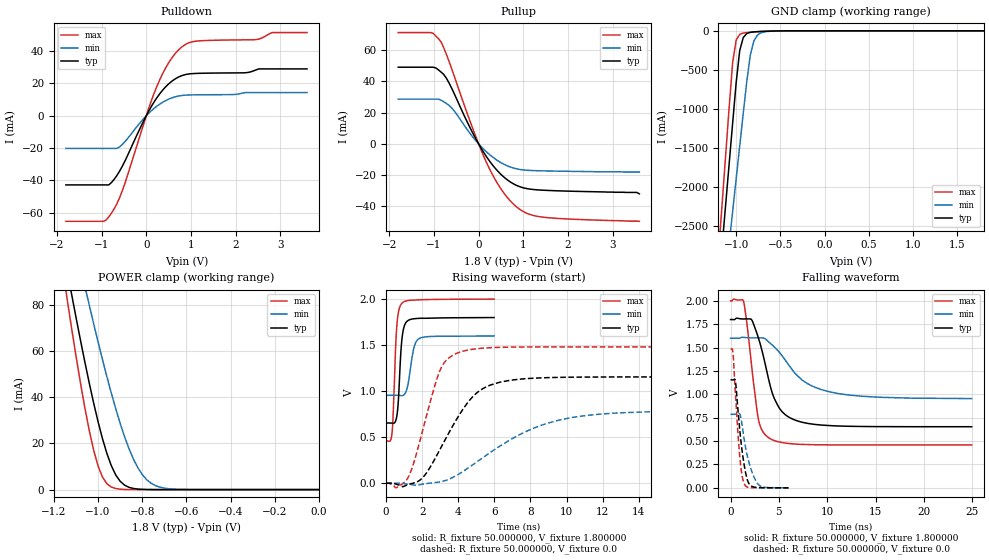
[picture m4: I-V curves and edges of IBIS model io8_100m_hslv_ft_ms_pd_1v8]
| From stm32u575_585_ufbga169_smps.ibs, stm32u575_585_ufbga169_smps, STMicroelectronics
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|   Model io8_100m_hslv_ft_ms_pd_1v8
[Model]  io8_100m_hslv_ft_ms_pd_1v8
Model_type I/O
Polarity   Non-Inverting
Enable   Active-Low
Vinl =   0.540000V
Vinh =   1.260000V
Vmeas =  0.900000V
Cref =   50.000000pF
Rref =   100.000000M
Vref =   0.0V
C_comp   3.235100pF   3.233200pF   3.282800pF
[Temperature Range]   25.000000   0.140000k   -40.000000
[Pullup Reference]   1.800000V   1.600000V   2.000000V
[Pulldown Reference]   0.0V   0.0V   0.0V
[POWER Clamp Reference]   1.800000V   1.600000V   2.000000V
[GND Clamp Reference]   0.0V   0.0V   0.0V
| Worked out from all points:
|   slope of the pulldown table from 0 to 0.27 V, typ, clamps not added: 21.7 ohm
|   slope of the pullup table from 0 to 0.27 V, typ, clamps not added: 22.6 ohm
|   GND clamp passes 1 mA (typ) near -0.51 V on its own axis
|   POWER clamp passes 1 mA (typ) near -0.86 V on its own axis
|   rising waveform, R_fixture 50.000000, V_fixture 1.800000: 20-80 % time 207ps typ, 320ps min, 193ps max; typ from 0.654 V to 1.8 V
|   rising waveform, R_fixture 50.000000, V_fixture 0.0: 20-80 % time 2.12ns typ, 4.11ns min, 1.26ns max; typ from 0 V to 1.15 V
|   falling waveform, R_fixture 50.000000, V_fixture 1.800000: 20-80 % time 1.9ns typ, 3.69ns min, 1.06ns max; typ from 1.8 V to 0.654 V
|   falling waveform, R_fixture 50.000000, V_fixture 0.0: 20-80 % time 740ps typ, 1.01ns min, 587ps max; typ from 1.15 V to 0 V
[Pulldown]
|Voltage   I(typ)   I(min)   I(max)
-1.8V     -42.74mA   -20.21mA   -65.25mA
-960mV    -42.74mA   -20.21mA   -65.25mA
-780mV    -41.3mA    -20.21mA   -60.25mA
-540mV    -31.39mA   -17.82mA   -46.65mA
0V        0A         -500fA     0A
240mV     11.28mA    6.002mA    18.38mA
480mV     19.17mA    10.02mA    31.83mA
780mV     24.67mA    12.5mA     42.21mA
1.14V     26.24mA    12.99mA    46.23mA
2.46V     28.42mA    14.39mA    47.14mA
2.82V     29mA       14.39mA    51.49mA
3.6V      29mA       14.39mA    51.49mA
[Pullup]
|Voltage   I(typ)   I(min)   I(max)
-1.8V     49.08mA    28.63mA    71.26mA
-1.08V    49.08mA    28.63mA    71.26mA
-840mV    45.95mA    27.95mA    65.26mA
-720mV    41.97mA    25.84mA    57.25mA
-600mV    35.46mA    22.93mA    47.86mA
-180mV    9.685mA    6.268mA    13.58mA
180mV     -8.368mA   -5.234mA   -12.14mA
540mV     -20.62mA   -12.68mA   -30.5mA
900mV     -27.22mA   -16.28mA   -41.49mA
1.14V     -28.94mA   -17mA      -45.14mA
1.5V      -29.77mA   -17.34mA   -47.14mA
3.6V      -32mA      -18mA      -49.6mA
[GND_clamp]
|Voltage   I(typ)   I(min)   I(max)
-1.8V     -9.707A    -9.942A    -9.774A
-1.2V     -3.309A    -4.006A    -2.865A
-1.16V    -2.777A    -3.584A    -2.239A
-1.12V    -2.246A    -3.162A    -1.614A
-1.04V    -1.186A    -2.319A    -408.7mA
-1V       -663.9mA   -1.898A    -117.8mA
-960mV    -254mA     -1.478A    -45.15mA
-920mV    -86.04mA   -1.06A     -28.6mA
-840mV    -19.13mA   -308.9mA   -18.75mA
-800mV    -13.4mA    -130.8mA   -15.33mA
-720mV    -7.959mA   -25.38mA   -9.395mA
1.8V      45.71uA    33.33uA    56.11uA
[POWER_clamp]
|Voltage   I(typ)   I(min)   I(max)
-1.8V     470.8mA    433.7mA    554.6mA
-1.14V    95.25mA    122.7mA    82.82mA
-1.12V    84.97mA    114mA      70.27mA
-1.06V    55.51mA    88.42mA    35.67mA
-1.04V    46.34mA    80.15mA    25.76mA
-1V       29.51mA    64.13mA    10.3mA
-940mV    10.39mA    41.86mA    1.109mA
-900mV    3.624mA    28.77mA    182.8uA
-840mV    490.7uA    13.24mA    11.35uA
-800mV    116.8uA    6.532mA    1.77uA
-740mV    13.2uA     1.723mA    109.2nA
0V        0A         18.72nA    0A
[Ramp]
| variable   typ   min   max
dV/dt_r  0.69258/2.11561n   0.47166/4.10833n   0.88824/1.25611n
dV/dt_f  0.68753/1.89816n   0.38638/3.68861n   0.92451/1.05360n
R_load = 50.000000
[Rising Waveform]
R_fixture= 50.000000
V_fixture= 1.800000
V_fixture_min= 1.600000
V_fixture_max= 2.000000
|time   V(typ)   V(min)   V(max)
0s        653.5mV    954.4mV    458.5mV
324.3ps   652.2mV    954.5mV    542.6mV
384.4ps   650.4mV    954.6mV    733.3mV
588.6ps   725.8mV    954.7mV    1.702V
684.7ps   923.2mV    954.3mV    1.862V
852.9ps   1.521V     950.9mV    1.949V
1.105ns   1.747V     997.4mV    1.979V
1.55ns    1.786V     1.479V     1.988V
1.838ns   1.791V     1.572V     1.992V
5.982ns   1.799V     1.599V     1.999V
[Rising Waveform]
R_fixture= 50.000000
V_fixture= 0.0
V_fixture_min= 0.0
V_fixture_max= 0.0
|time   V(typ)   V(min)   V(max)
0s        -90.96uV   -18.92uV   -77.39uV
550.6ps   -10.41mV   -58.52uV   -50.74mV
1.201ns   -16.55mV   -11.09mV   57.53mV
2.052ns   65.95mV    -8.993mV   595.3mV
2.953ns   355.7mV    13.27mV    1.211V
4.154ns   772.8mV    114.4mV    1.428V
5.055ns   985.9mV    235.1mV    1.461V
6.106ns   1.086V     378.1mV    1.475V
10.56ns   1.152V     721.4mV    1.48V
24.92ns   1.155V     786.3mV    1.48V
[Falling Waveform]
R_fixture= 50.000000
V_fixture= 1.800000
V_fixture_min= 1.600000
V_fixture_max= 2.000000
|time   V(typ)   V(min)   V(max)
0s        1.799V     1.599V     1.999V
1.351ns   1.806V     1.609V     1.992V
2.152ns   1.801V     1.603V     1.329V
2.853ns   1.611V     1.604V     748.6mV
4.054ns   1.11V      1.55V      528.2mV
4.805ns   896.7mV    1.477V     496.3mV
5.656ns   782.5mV    1.366V     478.6mV
7.357ns   702.4mV    1.156V     464.7mV
9.409ns   671.2mV    1.05V      460mV
24.92ns   653.5mV    954.4mV    458.5mV
[Falling Waveform]
R_fixture= 50.000000
V_fixture= 0.0
V_fixture_min= 0.0
V_fixture_max= 0.0
|time   V(typ)   V(min)   V(max)
0s        1.155V     786.3mV    1.48V
240.2ps   1.154V     786.3mV    1.452V
492.5ps   1.144V     786.5mV    1.018V
768.8ps   829.6mV    789.4mV    575.7mV
973ps     599.1mV    787mV      313.4mV
1.189ns   399.9mV    673.5mV    131.5mV
1.393ns   254.7mV    528.7mV    50.36mV
1.886ns   48.23mV    276.8mV    4.615mV
2.823ns   3.338mV    42.85mV    1.237mV
5.982ns   -90.96uV   -18.92uV   -77.39uV
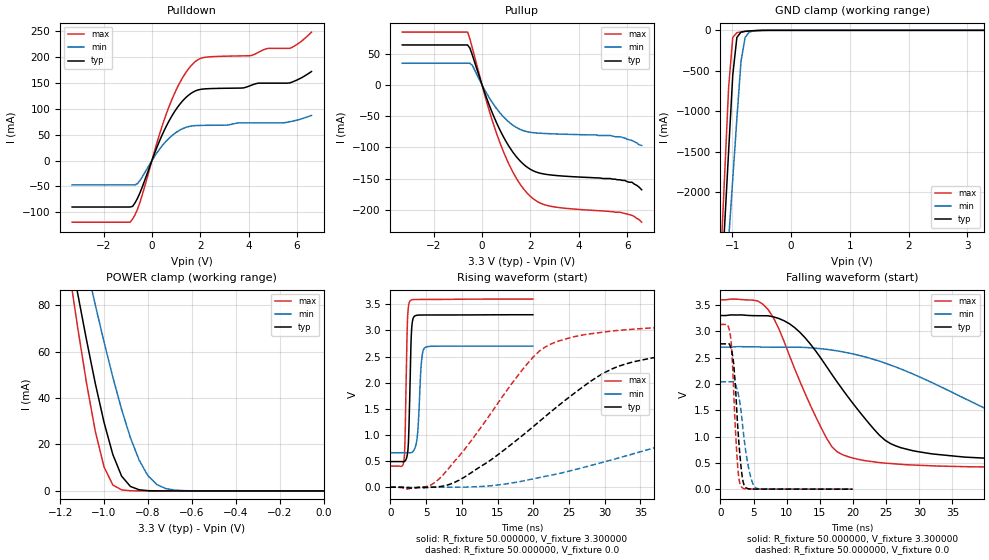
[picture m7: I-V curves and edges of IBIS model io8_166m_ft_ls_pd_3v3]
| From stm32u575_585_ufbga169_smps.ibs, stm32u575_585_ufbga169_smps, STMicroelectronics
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|   Model io8_166m_ft_ls_pd_3v3
[Model]  io8_166m_ft_ls_pd_3v3
Model_type I/O
Polarity   Non-Inverting
Enable   Active-Low
Vinl =   0.990000V
Vinh =   2.310000V
Vmeas =  1.650000V
Cref =   50.000000pF
Rref =   100.000000M
Vref =   0.0V
C_comp   3.517100pF   3.489300pF   3.557700pF
[Temperature Range]   25.000000   0.140000k   -40.000000
[Pullup Reference]   3.300000V   2.700000V   3.600000V
[Pulldown Reference]   0.0V   0.0V   0.0V
[POWER Clamp Reference]   3.300000V   2.700000V   3.600000V
[GND Clamp Reference]   0.0V   0.0V   0.0V
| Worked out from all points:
|   slope of the pulldown table from 0 to 0.495 V, typ, clamps not added: 8.73 ohm
|   slope of the pullup table from 0 to 0.495 V, typ, clamps not added: 9.64 ohm
|   GND clamp passes 1 mA (typ) near -0.50 V on its own axis
|   POWER clamp passes 1 mA (typ) near -0.85 V on its own axis
|   rising waveform, R_fixture 50.000000, V_fixture 3.300000: 20-80 % time 307ps typ, 454ps min, 272ps max; typ from 0.49 V to 3.3 V
|   rising waveform, R_fixture 50.000000, V_fixture 0.0: 20-80 % time 15.9ns typ, 34.2ns min, 10.3ns max; typ from 0 V to 2.76 V
|   falling waveform, R_fixture 50.000000, V_fixture 3.300000: 20-80 % time 10.1ns typ, 22.3ns min, 6.6ns max; typ from 3.3 V to 0.49 V
|   falling waveform, R_fixture 50.000000, V_fixture 0.0: 20-80 % time 897ps typ, 1.3ns min, 735ps max; typ from 2.76 V to 0 V
[Pulldown]
|Voltage   I(typ)   I(min)   I(max)
-3.3V     -89.72mA   -47.06mA   -119mA
-900mV    -89.72mA   -47.06mA   -119mA
-500mV    -62.92mA   -38.71mA   -81.44mA
300mV     36.2mA     21.01mA    48.7mA
800mV     84.07mA    46.96mA    114.9mA
1.3V      116.7mA    62.09mA    162.4mA
1.8V      134.4mA    67.39mA    191.2mA
2.3V      138.6mA    67.98mA    199.8mA
4.1V      145.1mA    72.78mA    202.7mA
4.8V      149.4mA    72.78mA    216.5mA
5.7V      149.8mA    74.8mA     216.5mA
6.6V      171.9mA    87.1mA     247.9mA
[Pullup]
|Voltage   I(typ)   I(min)   I(max)
-3.3V     64.11mA    34.77mA    84.74mA
-600mV    64.11mA    34.77mA    84.74mA
-400mV    47.78mA    31.25mA    59.06mA
300mV     -32.62mA   -20.62mA   -41.63mA
800mV     -76.87mA   -47.45mA   -98.74mA
1.4V      -114.1mA   -67.68mA   -148.3mA
1.7V      -126.6mA   -73.14mA   -165.7mA
2.1V      -137.3mA   -76.42mA   -182mA
3V        -144.9mA   -78.48mA   -195.5mA
5.9V      -153mA     -85mA      -206mA
6.2V      -156mA     -89mA      -209mA
6.6V      -168mA     -97mA      -220mA
[GND_clamp]
|Voltage   I(typ)   I(min)   I(max)
-3.3V     -9.098A    -9.372A    -9.671A
-1.2V     -3.386A    -4.091A    -2.933A
-1.13V    -2.437A    -3.34A     -1.815A
-1.06V    -1.49A     -2.588A    -705.6mA
-990mV    -555.7mA   -1.839A    -89.05mA
-920mV    -88.14mA   -1.093A    -28.79mA
-850mV    -22.37mA   -387.4mA   -19.86mA
-780mV    -12.13mA   -88.01mA   -13.89mA
-710mV    -7.72mA    -22.53mA   -8.86mA
-640mV    -4.556mA   -7.872mA   -4.884mA
-360mV    -39.7uA    -179.9uA   -19.45uA
3.28V     83.52uA    56.87uA    102.4uA
[POWER_clamp]
|Voltage   I(typ)   I(min)   I(max)
-3.28V    1.355A     1.167A     1.664A
-1.16V    105.7mA    131.6mA    95.69mA
-1.12V    84.97mA    114mA      70.27mA
-1.08V    65.05mA    96.83mA    46.54mA
-1.04V    46.34mA    80.15mA    25.76mA
-1V       29.51mA    64.13mA    10.3mA
-960mV    15.69mA    48.99mA    2.571mA
-920mV    6.373mA    35.1mA     455.6uA
-840mV    490.7uA    13.24mA    11.36uA
-760mV    27.33uA    2.767mA    278.2nA
-640mV    347.6nA    134.1uA    16.76nA
0V        0A         19.95nA    0A
[Ramp]
| variable   typ   min   max
dV/dt_r  1.65672/15.83283n   1.22418/34.20511n   1.87818/10.27070n
dV/dt_f  1.68577/10.07893n   1.22392/22.27950n   1.91752/6.57604n
R_load = 50.000000
[Rising Waveform]
R_fixture= 50.000000
V_fixture= 3.300000
V_fixture_min= 2.700000
V_fixture_max= 3.600000
|time   V(typ)   V(min)   V(max)
0s        489.8mV    659.5mV    403.4mV
1.922ns   489.5mV    659.5mV    523.7mV
2.042ns   498.3mV    659.5mV    806.3mV
2.402ns   639.8mV    659.3mV    3.175V
2.763ns   1.96V      658.3mV    3.562V
3.123ns   3.191V     676.2mV    3.588V
3.764ns   3.29V      946.9mV    3.591V
4.364ns   3.294V     2.402V     3.592V
4.845ns   3.294V     2.67V      3.592V
19.94ns   3.299V     2.699V     3.599V
[Rising Waveform]
R_fixture= 50.000000
V_fixture= 0.0
V_fixture_min= 0.0
V_fixture_max= 0.0
|time   V(typ)   V(min)   V(max)
0s        15.39nV    112.3nV    48.72nV
6.406ns   3.48mV     -601.2uV   105.4mV
13.61ns   478mV      20.14mV    1.322V
18.42ns   981.5mV    115.1mV    2.236V
21.62ns   1.346V     206.1mV    2.678V
29.63ns   2.168V     472.6mV    2.964V
36.84ns   2.477V     750.2mV    3.049V
63.26ns   2.712V     1.657V     3.121V
95.3ns    2.754V     1.937V     3.129V
398.8ns   2.761V     2.04V      3.13V
[Falling Waveform]
R_fixture= 50.000000
V_fixture= 3.300000
V_fixture_min= 2.700000
V_fixture_max= 3.600000
|time   V(typ)   V(min)   V(max)
0s        3.299V     2.699V     3.599V
5.606ns   3.296V     2.704V     3.578V
7.207ns   3.295V     2.698V     3.412V
12.01ns   2.978V     2.696V     2.042V
17.62ns   2.035V     2.628V     709.6mV
24.02ns   1.02V      2.43V      504.3mV
28.03ns   761.9mV    2.242V     464.7mV
49.65ns   540.7mV    1.059V     410.4mV
81.68ns   498.4mV    756.2mV    404.1mV
398.8ns   489.8mV    659.5mV    403.4mV
[Falling Waveform]
R_fixture= 50.000000
V_fixture= 0.0
V_fixture_min= 0.0
V_fixture_max= 0.0
|time   V(typ)   V(min)   V(max)
0s        2.761V     2.04V      3.13V
1.001ns   2.761V     2.04V      3.133V
1.522ns   2.707V     2.04V      2.907V
2.002ns   2.376V     2.044V     1.864V
2.563ns   1.293V     1.882V     509.3mV
2.843ns   794.5mV    1.715V     165.3mV
3.203ns   321.5mV    1.38V      37.65mV
4.244ns   7.792mV    410.8mV    2.284mV
5.325ns   1.171mV    26.6mV     1.552mV
19.94ns   15.39nV    112.3nV    48.72nV
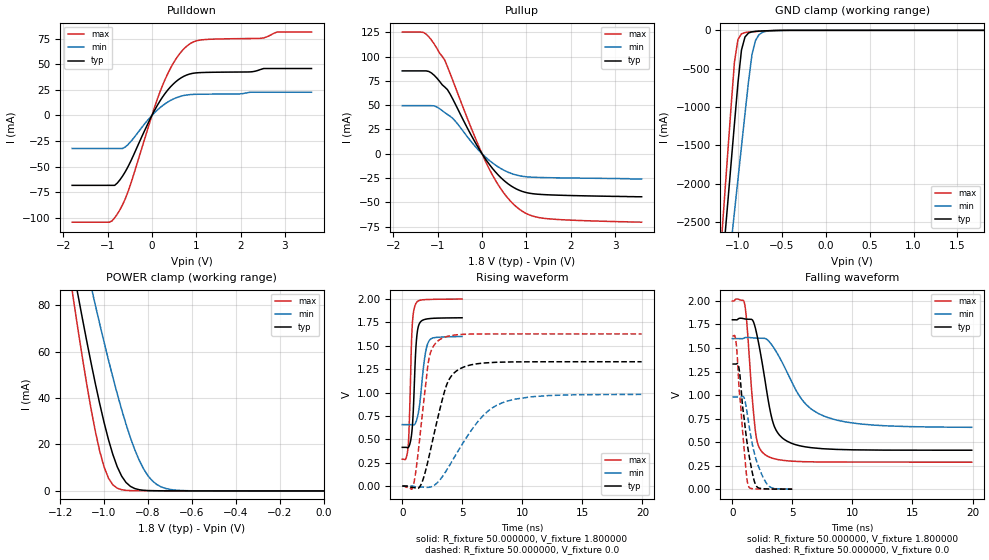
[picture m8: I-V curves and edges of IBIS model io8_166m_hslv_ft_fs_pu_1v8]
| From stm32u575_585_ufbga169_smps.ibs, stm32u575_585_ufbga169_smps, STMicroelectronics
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|   Model io8_166m_hslv_ft_fs_pu_1v8
[Model]  io8_166m_hslv_ft_fs_pu_1v8
Model_type I/O
Polarity   Non-Inverting
Enable   Active-Low
Vinl =   0.540000V
Vinh =   1.260000V
Vmeas =  0.900000V
Cref =   50.000000pF
Rref =   100.000000M
Vref =   0.0V
C_comp   3.358400pF   3.352800pF   3.400400pF
[Temperature Range]   25.000000   0.140000k   -40.000000
[Pullup Reference]   1.800000V   1.600000V   2.000000V
[Pulldown Reference]   0.0V   0.0V   0.0V
[POWER Clamp Reference]   1.800000V   1.600000V   2.000000V
[GND Clamp Reference]   0.0V   0.0V   0.0V
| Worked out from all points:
|   slope of the pulldown table from 0 to 0.27 V, typ, clamps not added: 13.6 ohm
|   slope of the pullup table from 0 to 0.27 V, typ, clamps not added: 15.9 ohm
|   GND clamp passes 1 mA (typ) near -0.51 V on its own axis
|   POWER clamp passes 1 mA (typ) near -0.86 V on its own axis
|   rising waveform, R_fixture 50.000000, V_fixture 1.800000: 20-80 % time 290ps typ, 497ps min, 236ps max; typ from 0.414 V to 1.8 V
|   rising waveform, R_fixture 50.000000, V_fixture 0.0: 20-80 % time 1.51ns typ, 3.17ns min, 854ps max; typ from 0 V to 1.33 V
|   falling waveform, R_fixture 50.000000, V_fixture 1.800000: 20-80 % time 1.2ns typ, 2.76ns min, 637ps max; typ from 1.8 V to 0.414 V
|   falling waveform, R_fixture 50.000000, V_fixture 0.0: 20-80 % time 791ps typ, 1.05ns min, 592ps max; typ from 1.33 V to 0 V
[Pulldown]
|Voltage   I(typ)   I(min)   I(max)
-1.8V     -68.38mA   -32.32mA   -104.4mA
-960mV    -68.38mA   -32.32mA   -104.4mA
-780mV    -66.08mA   -32.32mA   -96.43mA
-540mV    -50.22mA   -28.51mA   -74.66mA
0V        0A         0A         0A
240mV     18.04mA    9.6mA      29.42mA
480mV     30.68mA    16.02mA    50.95mA
780mV     39.48mA    19.99mA    67.56mA
1.14V     41.99mA    20.78mA    74.01mA
2.46V     45.1mA     22.69mA    75.45mA
2.82V     45.89mA    22.69mA    81.54mA
3.6V      45.89mA    22.69mA    81.54mA
[Pullup]
|Voltage   I(typ)   I(min)   I(max)
-1.8V     85.36mA    49.56mA    125.3mA
-1.32V    85.36mA    49.56mA    124.9mA
-1.08V    80.85mA    49.29mA    113.1mA
-840mV    68.7mA     42.35mA    96.38mA
-660mV    56.31mA    36.42mA    75.5mA
-180mV    13.77mA    8.913mA    19.32mA
180mV     -11.9mA    -7.442mA   -17.26mA
480mV     -26.98mA   -16.65mA   -39.76mA
840mV     -37.65mA   -22.63mA   -57.07mA
1.08V     -40.74mA   -24.01mA   -63.22mA
1.44V     -42.19mA   -24.58mA   -66.73mA
3.6V      -44.3mA    -26mA      -70.5mA
[GND_clamp]
|Voltage   I(typ)   I(min)   I(max)
-1.8V     -9.908A    -9.683A    -9.994A
-1.2V     -3.383A    -4.084A    -2.934A
-1.16V    -2.841A    -3.655A    -2.294A
-1.12V    -2.299A    -3.226A    -1.656A
-1.04V    -1.218A    -2.369A    -414.2mA
-1V       -684.7mA   -1.941A    -119.2mA
-960mV    -257.2mA   -1.514A    -45.66mA
-920mV    -87.03mA   -1.089A    -28.93mA
-840mV    -19.35mA   -312.8mA   -18.97mA
-800mV    -13.55mA   -132.4mA   -15.49mA
-720mV    -8.042mA   -25.67mA   -9.491mA
1.8V      0A         13.64nA    0A
[POWER_clamp]
|Voltage   I(typ)   I(min)   I(max)
-1.8V     470.9mA    433.7mA    554.6mA
-1.14V    95.28mA    122.7mA    82.88mA
-1.12V    85mA       114mA      70.34mA
-1.06V    55.55mA    88.43mA    35.73mA
-1.04V    46.38mA    80.17mA    25.83mA
-1V       29.54mA    64.14mA    10.37mA
-940mV    10.43mA    41.88mA    1.177mA
-900mV    3.66mA     28.79mA    250.5uA
-840mV    527.2uA    13.26mA    96.07uA
-800mV    154.2uA    6.55mA     88.1uA
-740mV    59.7uA     1.741mA    70.27uA
0V        0A         18.18nA    0A
[Ramp]
| variable   typ   min   max
dV/dt_r  0.79757/1.50753n   0.58780/3.16215n   0.97651/0.85245n
dV/dt_f  0.83132/1.19679n   0.56443/2.75362n   1.02743/0.63550n
R_load = 50.000000
[Rising Waveform]
R_fixture= 50.000000
V_fixture= 1.800000
V_fixture_min= 1.600000
V_fixture_max= 2.000000
|time   V(typ)   V(min)   V(max)
0s        414.4mV    657.5mV    287.7mV
500.5ps   413.3mV    657.7mV    438.2mV
590.6ps   433.7mV    657.7mV    696mV
810.8ps   592.5mV    656.4mV    1.663V
1.071ns   1.308V     666.2mV    1.934V
1.191ns   1.574V     702.8mV    1.964V
1.371ns   1.72V      805.8mV    1.983V
1.862ns   1.782V     1.367V     1.994V
2.192ns   1.79V      1.544V     1.996V
4.985ns   1.8V       1.6V       2V
[Rising Waveform]
R_fixture= 50.000000
V_fixture= 0.0
V_fixture_min= 0.0
V_fixture_max= 0.0
|time   V(typ)   V(min)   V(max)
0s        398.4uV    503.2uV    379.2uV
920.9ps   -14.26mV   -1.108mV   5.419mV
1.562ns   15.92mV    -10.29mV   636.8mV
2.202ns   301.5mV    -12.82mV   1.346V
3.123ns   816.4mV    64.35mV    1.567V
3.764ns   1.103V     184.7mV    1.602V
4.484ns   1.228V     340mV      1.617V
6.607ns   1.314V     735.9mV    1.627V
8.328ns   1.326V     890.7mV    1.628V
19.94ns   1.33V      980.7mV    1.628V
[Falling Waveform]
R_fixture= 50.000000
V_fixture= 1.800000
V_fixture_min= 1.600000
V_fixture_max= 2.000000
|time   V(typ)   V(min)   V(max)
0s        1.8V       1.6V       2V
1.001ns   1.81V      1.608V     1.98V
1.201ns   1.807V     1.613V     1.77V
1.962ns   1.687V     1.605V     576.1mV
2.763ns   1.12V      1.6V       363.3mV
3.323ns   735.4mV    1.525V     329.8mV
3.924ns   574.4mV    1.401V     312.2mV
5.846ns   455.3mV    943.9mV    292.7mV
7.808ns   428.1mV    767.4mV    288.9mV
19.94ns   414.4mV    657.5mV    287.7mV
[Falling Waveform]
R_fixture= 50.000000
V_fixture= 0.0
V_fixture_min= 0.0
V_fixture_max= 0.0
|time   V(typ)   V(min)   V(max)
0s        1.33V      980.7mV    1.628V
300.3ps   1.33V      980.8mV    1.566V
400.4ps   1.335V     980.8mV    1.428V
530.5ps   1.3V       980.8mV    1.129V
981ps     750.8mV    970.5mV    423.2mV
1.191ns   525.5mV    840.2mV    133.6mV
1.341ns   397mV      715.9mV    33mV
1.952ns   43.7mV     326.2mV    3.268mV
2.773ns   3.59mV     75.49mV    1.456mV
4.985ns   398.4uV    503.2uV    379.2uV
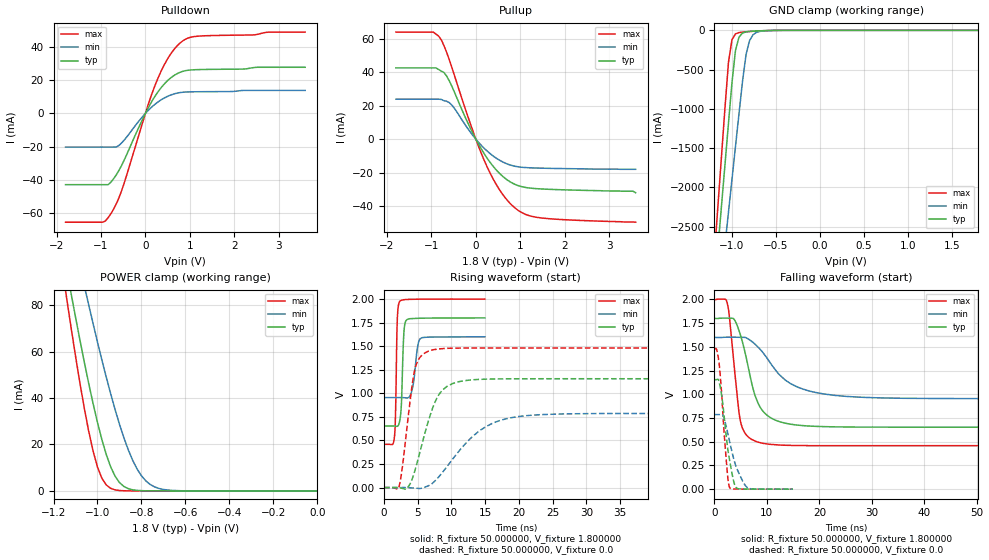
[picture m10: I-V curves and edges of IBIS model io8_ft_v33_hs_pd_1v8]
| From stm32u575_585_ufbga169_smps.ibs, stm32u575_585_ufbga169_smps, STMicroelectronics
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|   Model io8_ft_v33_hs_pd_1v8
[Model]  io8_ft_v33_hs_pd_1v8
Model_type I/O
Polarity   Non-Inverting
Enable   Active-Low
Vinl =   0.540000V
Vinh =   1.260000V
Vmeas =  0.900000V
Cref =   50.000000pF
Rref =   100.000000M
Vref =   0.0V
C_comp   3.087500pF   3.086600pF   3.135700pF
[Temperature Range]   25.000000   0.140000k   -40.000000
[Pullup Reference]   1.800000V   1.600000V   2.000000V
[Pulldown Reference]   0.0V   0.0V   0.0V
[POWER Clamp Reference]   1.800000V   1.600000V   2.000000V
[GND Clamp Reference]   0.0V   0.0V   0.0V
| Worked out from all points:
|   slope of the pulldown table from 0 to 0.27 V, typ, clamps not added: 21.7 ohm
|   slope of the pullup table from 0 to 0.27 V, typ, clamps not added: 22.6 ohm
|   GND clamp passes 1 mA (typ) near -0.51 V on its own axis
|   POWER clamp passes 1 mA (typ) near -0.86 V on its own axis
|   rising waveform, R_fixture 50.000000, V_fixture 1.800000: 20-80 % time 317ps typ, 630ps min, 229ps max; typ from 0.654 V to 1.8 V
|   rising waveform, R_fixture 50.000000, V_fixture 0.0: 20-80 % time 2.89ns typ, 6.11ns min, 1.52ns max; typ from 0 V to 1.15 V
|   falling waveform, R_fixture 50.000000, V_fixture 1.800000: 20-80 % time 3.27ns typ, 6.78ns min, 1.71ns max; typ from 1.8 V to 0.654 V
|   falling waveform, R_fixture 50.000000, V_fixture 0.0: 20-80 % time 1.6ns typ, 2.38ns min, 1.14ns max; typ from 1.15 V to 0 V
[Pulldown]
|Voltage   I(typ)   I(min)   I(max)
-1.8V     -42.74mA   -20.21mA   -65.25mA
-960mV    -42.74mA   -20.21mA   -65.25mA
-780mV    -41.3mA    -20.21mA   -60.25mA
-660mV    -37mA      -20.2mA    -54.5mA
-540mV    -31.39mA   -17.82mA   -46.65mA
0V        0A         0A         0A
240mV     11.28mA    6.002mA    18.38mA
480mV     19.17mA    10.02mA    31.83mA
780mV     24.67mA    12.5mA     42.21mA
960mV     25.9mA     12.9mA     45.21mA
1.14V     26.24mA    12.99mA    46.23mA
3.6V      27.69mA    13.82mA    48.79mA
[Pullup]
|Voltage   I(typ)   I(min)   I(max)
-1.8V     42.59mA    23.91mA    63.97mA
-960mV    42.59mA    23.91mA    63.97mA
-780mV    40.7mA     23.74mA    59.39mA
-660mV    37.78mA    22.66mA    52mA
-540mV    31.58mA    20.34mA    42.81mA
-120mV    6.338mA    4.065mA    8.965mA
180mV     -8.368mA   -5.234mA   -12.14mA
540mV     -20.62mA   -12.68mA   -30.5mA
900mV     -27.22mA   -16.28mA   -41.49mA
1.14V     -28.94mA   -17mA      -45.14mA
1.5V      -29.77mA   -17.34mA   -47.14mA
3.6V      -32mA      -18mA      -49.6mA
[GND_clamp]
|Voltage   I(typ)   I(min)   I(max)
-1.8V     -9.707A    -9.942A    -9.774A
-1.2V     -3.309A    -4.006A    -2.865A
-1.16V    -2.777A    -3.584A    -2.239A
-1.12V    -2.246A    -3.162A    -1.614A
-1.04V    -1.186A    -2.319A    -408.7mA
-1V       -663.9mA   -1.898A    -117.8mA
-960mV    -254mA     -1.478A    -45.15mA
-920mV    -86.04mA   -1.06A     -28.6mA
-840mV    -19.13mA   -308.9mA   -18.75mA
-800mV    -13.4mA    -130.8mA   -15.33mA
-720mV    -7.959mA   -25.38mA   -9.395mA
1.8V      45.71uA    33.33uA    56.11uA
[POWER_clamp]
|Voltage   I(typ)   I(min)   I(max)
-1.8V     470.8mA    433.7mA    554.6mA
-1.14V    95.25mA    122.7mA    82.82mA
-1.12V    84.97mA    114mA      70.27mA
-1.06V    55.51mA    88.42mA    35.67mA
-1.04V    46.34mA    80.15mA    25.76mA
-1V       29.51mA    64.13mA    10.3mA
-940mV    10.39mA    41.86mA    1.109mA
-900mV    3.624mA    28.77mA    182.8uA
-840mV    490.7uA    13.24mA    11.35uA
-800mV    116.8uA    6.532mA    1.77uA
-740mV    13.2uA     1.723mA    109.3nA
0V        0A         18.72nA    0A
[Ramp]
| variable   typ   min   max
dV/dt_r  0.69258/2.88459n   0.47170/6.10262n   0.88830/1.51750n
dV/dt_f  0.68753/3.27006n   0.38693/6.77240n   0.92451/1.71172n
R_load = 50.000000
[Rising Waveform]
R_fixture= 50.000000
V_fixture= 1.800000
V_fixture_min= 1.600000
V_fixture_max= 2.000000
|time   V(typ)   V(min)   V(max)
0s        653.5mV    954.4mV    458.5mV
1.562ns   653mV      954.4mV    540.9mV
1.712ns   651.7mV    954.5mV    778.9mV
1.982ns   650.3mV    954.5mV    1.791V
2.342ns   710mV      954.4mV    1.975V
2.583ns   884.8mV    954.2mV    1.987V
2.943ns   1.63V      953.3mV    1.992V
3.333ns   1.776V     950.4mV    1.995V
5.345ns   1.796V     1.576V     1.998V
14.95ns   1.799V     1.599V     1.999V
[Rising Waveform]
R_fixture= 50.000000
V_fixture= 0.0
V_fixture_min= 0.0
V_fixture_max= 0.0
|time   V(typ)   V(min)   V(max)
0s        4.575uV    -1.131uV   13.19uV
2.242ns   -3.065mV   5.74uV     10.23mV
3.524ns   3.056mV    -685.9uV   709.3mV
4.645ns   194.7mV    -6.053mV   1.274V
7.207ns   841.6mV    46.63mV    1.46V
8.328ns   1.004V     130.5mV    1.472V
10.25ns   1.105V     308.4mV    1.478V
14.41ns   1.148V     614.3mV    1.48V
19.86ns   1.154V     752.2mV    1.48V
79.76ns   1.154V     786.2mV    1.48V
[Falling Waveform]
R_fixture= 50.000000
V_fixture= 1.800000
V_fixture_min= 1.600000
V_fixture_max= 2.000000
|time   V(typ)   V(min)   V(max)
0s        1.799V     1.599V     1.999V
2.402ns   1.803V     1.602V     1.969V
2.883ns   1.802V     1.602V     1.804V
3.684ns   1.795V     1.602V     1.347V
4.965ns   1.625V     1.601V     714.9mV
6.086ns   1.379V     1.595V     571.2mV
8.168ns   926.4mV    1.505V     497.9mV
13.61ns   694.2mV    1.145V     462.8mV
20.66ns   659.7mV    1.005V     458.8mV
79.76ns   653.5mV    954.4mV    458.5mV
[Falling Waveform]
R_fixture= 50.000000
V_fixture= 0.0
V_fixture_min= 0.0
V_fixture_max= 0.0
|time   V(typ)   V(min)   V(max)
0s        1.154V     786.2mV    1.48V
420.4ps   1.154V     786.2mV    1.471V
930.9ps   1.123V     786mV      1.307V
1.622ns   887.7mV    779.1mV    785.5mV
2.372ns   500mV      632mV      230.8mV
2.673ns   376.1mV    557.7mV    68.41mV
2.943ns   290.1mV    490.2mV    12.75mV
4.024ns   25.08mV    255mV      1.526mV
6.276ns   1.141mV    16.69mV    507.6uV
14.95ns   4.575uV    -1.131uV   13.19uV
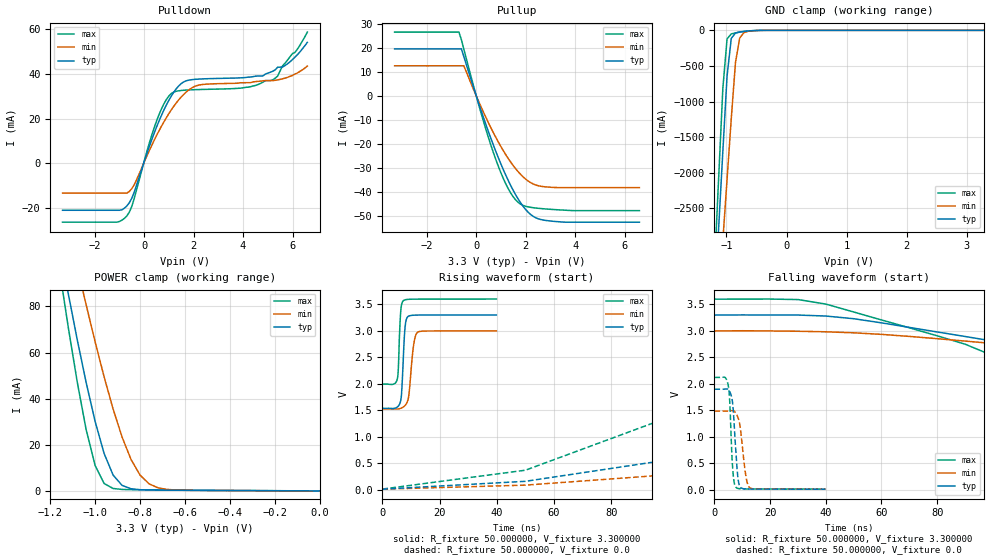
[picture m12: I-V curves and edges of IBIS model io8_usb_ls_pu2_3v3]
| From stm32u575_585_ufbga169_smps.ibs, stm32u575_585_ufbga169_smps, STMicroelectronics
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|   Model io8_usb_ls_pu2_3v3
[Model]  io8_usb_ls_pu2_3v3
Model_type I/O
Polarity   Non-Inverting
Enable   Active-Low
Vinl =   0.990000V
Vinh =   2.310000V
Vmeas =  1.650000V
Cref =   50.000000pF
Rref =   100.000000M
Vref =   0.0V
C_comp   7.156600pF   7.055100pF   7.302500pF
[Temperature Range]   25.000000   0.140000k   -40.000000
[Pullup Reference]   3.300000V   3.000000V   3.600000V
[Pulldown Reference]   0.0V   0.0V   0.0V
[POWER Clamp Reference]   3.300000V   3.000000V   3.600000V
[GND Clamp Reference]   0.0V   0.0V   0.0V
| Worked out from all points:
|   slope of the pulldown table from 0 to 0.495 V, typ, clamps not added: 32.2 ohm
|   slope of the pullup table from 0 to 0.495 V, typ, clamps not added: 33.1 ohm
|   GND clamp passes 1 mA (typ) near -0.45 V on its own axis
|   POWER clamp passes 1 mA (typ) near -0.84 V on its own axis
|   rising waveform, R_fixture 50.000000, V_fixture 3.300000: 20-80 % time 960ps typ, 1.52ns min, 701ps max; typ from 1.54 V to 3.3 V
|   rising waveform, R_fixture 50.000000, V_fixture 0.0: 20-80 % time 90.2ns typ, 130ns min, 66.7ns max; typ from 0.016 V to 1.9 V
|   falling waveform, R_fixture 50.000000, V_fixture 3.300000: 20-80 % time 79.3ns typ, 126ns min, 50.7ns max; typ from 3.3 V to 1.54 V
|   falling waveform, R_fixture 50.000000, V_fixture 0.0: 20-80 % time 1.41ns typ, 1.93ns min, 1.05ns max; typ from 1.9 V to 0.016 V
[Pulldown]
|Voltage   I(typ)   I(min)   I(max)
-3.3V     -21.06mA   -13.39mA   -26.4mA
-1.1V     -21.06mA   -13.39mA   -26.4mA
-700mV    -19.13mA   -13.39mA   -23.61mA
-400mV    -12.95mA   -9.641mA   -15.76mA
200mV     7.166mA    5.401mA    8.653mA
700mV     21.41mA    16.54mA    24.29mA
1.1V      30.09mA    23.9mA     31.2mA
1.5V      35.65mA    29.65mA    32.56mA
2.3V      37.71mA    35.15mA    33.01mA
5.2V      41.15mA    36.98mA    37.32mA
5.9V      45.4mA     38.89mA    47.66mA
6.6V      54.1mA     43.5mA     58.7mA
[Pullup]
|Voltage   I(typ)   I(min)   I(max)
-3.3V     19.5mA     12.47mA    26.48mA
-700mV    19.5mA     12.47mA    26.48mA
-600mV    19.5mA     12.47mA    23.34mA
-500mV    16.3mA     12.47mA    19.38mA
200mV     -6.226mA   -4.703mA   -7.327mA
700mV     -20.66mA   -15.47mA   -23.79mA
1.2V      -33.12mA   -24.56mA   -36.72mA
1.5V      -39.4mA    -29.07mA   -42.08mA
1.7V      -42.99mA   -31.61mA   -44.36mA
2.2V      -49.35mA   -36.11mA   -46.39mA
2.7V      -51.65mA   -37.76mA   -46.97mA
6.6V      -52.57mA   -38.16mA   -47.77mA
[GND_clamp]
|Voltage   I(typ)   I(min)   I(max)
-3.3V     -9.287A    -9.833A    -9.745A
-1.2V     -3.857A    -4.664A    -3.345A
-1.13V    -2.774A    -3.805A    -2.072A
-1.06V    -1.695A    -2.947A    -813.1mA
-990mV    -641.8mA   -2.091A    -120.9mA
-920mV    -113.3mA   -1.238A    -49.89mA
-850mV    -36.8mA    -452mA     -36.31mA
-780mV    -22.65mA   -108.9mA   -26.22mA
-710mV    -15.23mA   -32.27mA   -17.43mA
-570mV    -5.119mA   -7.032mA   -4.907mA
-360mV    -90.45uA   -461.6uA   -25.95uA
3.28V     0A         40.32nA    -16.18nA
[POWER_clamp]
|Voltage   I(typ)   I(min)   I(max)
-3.28V    1.356A     1.167A     1.665A
-1.16V    106.4mA    132.1mA    96.52mA
-1.12V    85.6mA     114.5mA    71.06mA
-1.08V    65.66mA    97.31mA    47.29mA
-1.04V    46.92mA    80.61mA    26.47mA
-1V       30.05mA    64.57mA    10.98mA
-960mV    16.21mA    49.41mA    3.211mA
-920mV    6.863mA    35.49mA    1.059mA
-840mV    925uA      13.6mA     543.5uA
-760mV    407uA      3.079mA    463.6uA
-640mV    303.3uA    387.1uA    366.5uA
0V        0A         50.45nA    0A
[Ramp]
| variable   typ   min   max
dV/dt_r  1.13113/80.14018n   0.88421/0.12391u   1.26403/53.70160n
dV/dt_f  1.05636/78.95644n   0.88302/0.12539u   0.96228/50.73040n
R_load = 50.000000
[Rising Waveform]
R_fixture= 50.000000
V_fixture= 3.300000
V_fixture_min= 3.000000
V_fixture_max= 3.600000
|time   V(typ)   V(min)   V(max)
0s        1.539V     1.528V     1.996V
5.205ns   1.564V     1.527V     2.09V
5.606ns   1.584V     1.527V     2.314V
6.326ns   1.666V     1.538V     3.296V
6.807ns   1.897V     1.549V     3.514V
7.928ns   3.06V      1.593V     3.585V
8.969ns   3.27V      1.703V     3.594V
10.89ns   3.295V     2.718V     3.598V
12.25ns   3.298V     2.971V     3.599V
39.88ns   3.3V       3V         3.6V
[Rising Waveform]
R_fixture= 50.000000
V_fixture= 0.0
V_fixture_min= 0.0
V_fixture_max= 0.0
|time   V(typ)   V(min)   V(max)
0s        15.58mV    15.62mV    17.28mV
50.05ns   163.8mV    91.64mV    373.4mV
100.1ns   568.9mV    287.5mV    1.371V
150.2ns   1.322V     547.2mV    2.207V
200.2ns   1.871V     925.8mV    2.229V
250.2ns   1.924V     1.324V     2.225V
300.3ns   1.927V     1.446V     2.22V
400.4ns   1.924V     1.475V     2.21V
2.052us   1.903V     1.489V     2.133V
4.955us   1.901V     1.489V     2.124V
[Falling Waveform]
R_fixture= 50.000000
V_fixture= 3.300000
V_fixture_min= 3.000000
V_fixture_max= 3.600000
|time   V(typ)   V(min)   V(max)
0s        3.3V       3V         3.6V
40.04ns   3.282V     2.984V     3.507V
90.09ns   2.896V     2.809V     2.75V
120.1ns   2.622V     2.668V     1.943V
140.1ns   2.376V     2.568V     1.81V
170.2ns   1.759V     2.402V     1.826V
200.2ns   1.556V     2.174V     1.851V
270.3ns   1.516V     1.673V     1.894V
400.4ns   1.524V     1.538V     1.942V
4.985us   1.539V     1.528V     1.996V
[Falling Waveform]
R_fixture= 50.000000
V_fixture= 0.0
V_fixture_min= 0.0
V_fixture_max= 0.0
|time   V(typ)   V(min)   V(max)
0s        1.901V     1.489V     2.124V
4.885ns   1.9V       1.49V      1.99V
5.445ns   1.859V     1.494V     1.717V
6.246ns   1.733V     1.496V     677.5mV
6.647ns   1.58V      1.496V     349.6mV
7.848ns   614.5mV    1.435V     45.02mV
8.969ns   88.22mV    1.271V     24.69mV
11.21ns   20.28mV    290.3mV    20.03mV
12.49ns   18.2mV     52.13mV    19.29mV
39.88ns   15.58mV    15.62mV    17.28mV
